VERSION 5.8 ;
BUSBITCHARS "[]" ;
DIVIDERCHAR "/" ;
UNITS
    DATABASE MICRONS 1000 ;
END UNITS

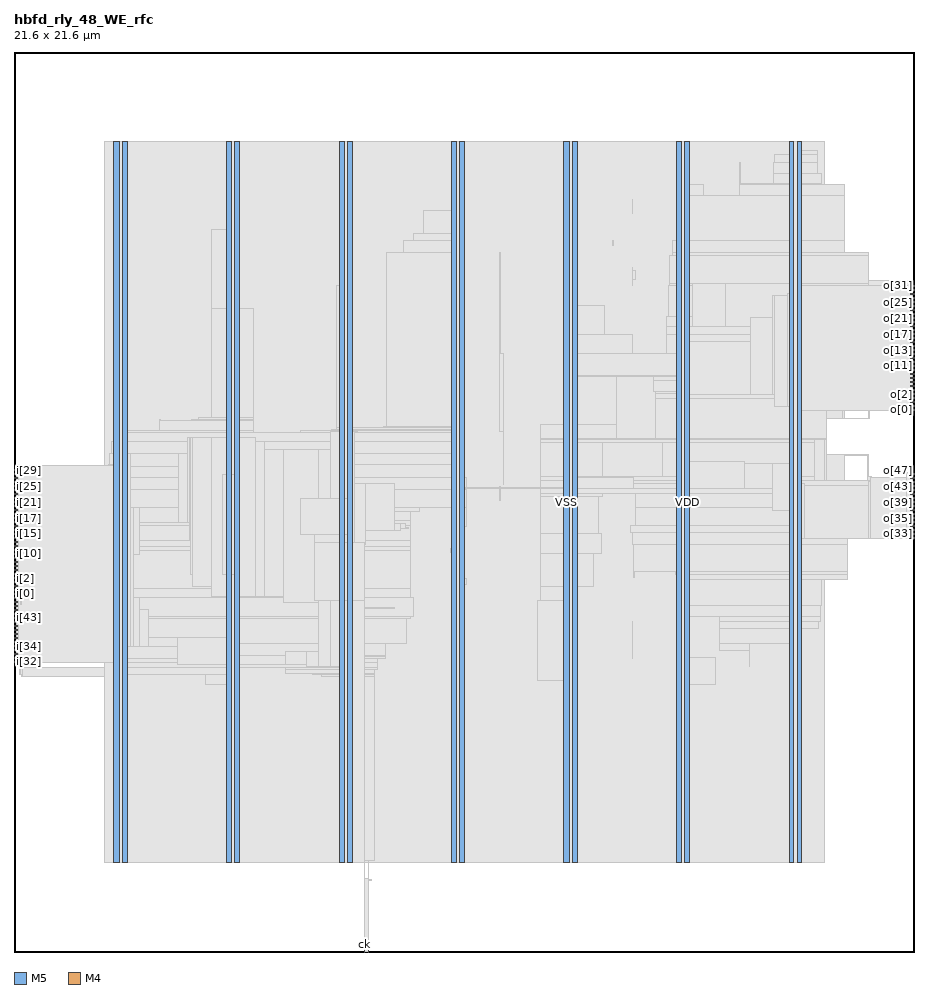
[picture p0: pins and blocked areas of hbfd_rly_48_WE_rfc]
MACRO hbfd_rly_48_WE_rfc
  FOREIGN hbfd_rly_48_WE_rfc 0 0 ;
  CLASS BLOCK ;
  SIZE 21.6 BY 21.6 ;
  PIN ck
    DIRECTION INPUT ;
    USE SIGNAL ;
    PORT
      LAYER M5 ;
        RECT  8.4 0 8.424 0.084 ;
    END
  END ck
  PIN i[0]
    DIRECTION INPUT ;
    USE SIGNAL ;
    PORT
      LAYER M4 ;
        RECT  0 8.592 0.084 8.616 ;
    END
  END i[0]
  PIN i[10]
    DIRECTION INPUT ;
    USE SIGNAL ;
    PORT
      LAYER M4 ;
        RECT  0 9.552 0.084 9.576 ;
    END
  END i[10]
  PIN i[11]
    DIRECTION INPUT ;
    USE SIGNAL ;
    PORT
      LAYER M4 ;
        RECT  0 9.648 0.084 9.672 ;
    END
  END i[11]
  PIN i[12]
    DIRECTION INPUT ;
    USE SIGNAL ;
    PORT
      LAYER M4 ;
        RECT  0 9.744 0.084 9.768 ;
    END
  END i[12]
  PIN i[13]
    DIRECTION INPUT ;
    USE SIGNAL ;
    PORT
      LAYER M4 ;
        RECT  0 9.84 0.084 9.864 ;
    END
  END i[13]
  PIN i[14]
    DIRECTION INPUT ;
    USE SIGNAL ;
    PORT
      LAYER M4 ;
        RECT  0 9.936 0.084 9.96 ;
    END
  END i[14]
  PIN i[15]
    DIRECTION INPUT ;
    USE SIGNAL ;
    PORT
      LAYER M4 ;
        RECT  0 10.032 0.084 10.056 ;
    END
  END i[15]
  PIN i[16]
    DIRECTION INPUT ;
    USE SIGNAL ;
    PORT
      LAYER M4 ;
        RECT  0 10.128 0.084 10.152 ;
    END
  END i[16]
  PIN i[17]
    DIRECTION INPUT ;
    USE SIGNAL ;
    PORT
      LAYER M4 ;
        RECT  0 10.224 0.084 10.248 ;
    END
  END i[17]
  PIN i[18]
    DIRECTION INPUT ;
    USE SIGNAL ;
    PORT
      LAYER M4 ;
        RECT  0 10.32 0.084 10.344 ;
    END
  END i[18]
  PIN i[19]
    DIRECTION INPUT ;
    USE SIGNAL ;
    PORT
      LAYER M4 ;
        RECT  0 10.416 0.084 10.44 ;
    END
  END i[19]
  PIN i[1]
    DIRECTION INPUT ;
    USE SIGNAL ;
    PORT
      LAYER M4 ;
        RECT  0 8.688 0.084 8.712 ;
    END
  END i[1]
  PIN i[20]
    DIRECTION INPUT ;
    USE SIGNAL ;
    PORT
      LAYER M4 ;
        RECT  0 10.512 0.084 10.536 ;
    END
  END i[20]
  PIN i[21]
    DIRECTION INPUT ;
    USE SIGNAL ;
    PORT
      LAYER M4 ;
        RECT  0 10.608 0.084 10.632 ;
    END
  END i[21]
  PIN i[22]
    DIRECTION INPUT ;
    USE SIGNAL ;
    PORT
      LAYER M4 ;
        RECT  0 10.704 0.084 10.728 ;
    END
  END i[22]
  PIN i[23]
    DIRECTION INPUT ;
    USE SIGNAL ;
    PORT
      LAYER M4 ;
        RECT  0 10.8 0.084 10.824 ;
    END
  END i[23]
  PIN i[24]
    DIRECTION INPUT ;
    USE SIGNAL ;
    PORT
      LAYER M4 ;
        RECT  0 10.896 0.084 10.92 ;
    END
  END i[24]
  PIN i[25]
    DIRECTION INPUT ;
    USE SIGNAL ;
    PORT
      LAYER M4 ;
        RECT  0 10.992 0.084 11.016 ;
    END
  END i[25]
  PIN i[26]
    DIRECTION INPUT ;
    USE SIGNAL ;
    PORT
      LAYER M4 ;
        RECT  0 11.088 0.084 11.112 ;
    END
  END i[26]
  PIN i[27]
    DIRECTION INPUT ;
    USE SIGNAL ;
    PORT
      LAYER M4 ;
        RECT  0 11.184 0.084 11.208 ;
    END
  END i[27]
  PIN i[28]
    DIRECTION INPUT ;
    USE SIGNAL ;
    PORT
      LAYER M4 ;
        RECT  0 11.28 0.084 11.304 ;
    END
  END i[28]
  PIN i[29]
    DIRECTION INPUT ;
    USE SIGNAL ;
    PORT
      LAYER M4 ;
        RECT  0 11.376 0.084 11.4 ;
    END
  END i[29]
  PIN i[2]
    DIRECTION INPUT ;
    USE SIGNAL ;
    PORT
      LAYER M4 ;
        RECT  0 8.784 0.084 8.808 ;
    END
  END i[2]
  PIN i[30]
    DIRECTION INPUT ;
    USE SIGNAL ;
    PORT
      LAYER M4 ;
        RECT  0 11.472 0.084 11.496 ;
    END
  END i[30]
  PIN i[31]
    DIRECTION INPUT ;
    USE SIGNAL ;
    PORT
      LAYER M4 ;
        RECT  0 11.568 0.084 11.592 ;
    END
  END i[31]
  PIN i[32]
    DIRECTION INPUT ;
    USE SIGNAL ;
    PORT
      LAYER M4 ;
        RECT  0 6.96 0.084 6.984 ;
    END
  END i[32]
  PIN i[33]
    DIRECTION INPUT ;
    USE SIGNAL ;
    PORT
      LAYER M4 ;
        RECT  0 7.056 0.084 7.08 ;
    END
  END i[33]
  PIN i[34]
    DIRECTION INPUT ;
    USE SIGNAL ;
    PORT
      LAYER M4 ;
        RECT  0 7.152 0.084 7.176 ;
    END
  END i[34]
  PIN i[35]
    DIRECTION INPUT ;
    USE SIGNAL ;
    PORT
      LAYER M4 ;
        RECT  0 7.248 0.084 7.272 ;
    END
  END i[35]
  PIN i[36]
    DIRECTION INPUT ;
    USE SIGNAL ;
    PORT
      LAYER M4 ;
        RECT  0 7.344 0.084 7.368 ;
    END
  END i[36]
  PIN i[37]
    DIRECTION INPUT ;
    USE SIGNAL ;
    PORT
      LAYER M4 ;
        RECT  0 7.44 0.084 7.464 ;
    END
  END i[37]
  PIN i[38]
    DIRECTION INPUT ;
    USE SIGNAL ;
    PORT
      LAYER M4 ;
        RECT  0 7.536 0.084 7.56 ;
    END
  END i[38]
  PIN i[39]
    DIRECTION INPUT ;
    USE SIGNAL ;
    PORT
      LAYER M4 ;
        RECT  0 7.632 0.084 7.656 ;
    END
  END i[39]
  PIN i[3]
    DIRECTION INPUT ;
    USE SIGNAL ;
    PORT
      LAYER M4 ;
        RECT  0 8.88 0.084 8.904 ;
    END
  END i[3]
  PIN i[40]
    DIRECTION INPUT ;
    USE SIGNAL ;
    PORT
      LAYER M4 ;
        RECT  0 7.728 0.084 7.752 ;
    END
  END i[40]
  PIN i[41]
    DIRECTION INPUT ;
    USE SIGNAL ;
    PORT
      LAYER M4 ;
        RECT  0 7.824 0.084 7.848 ;
    END
  END i[41]
  PIN i[42]
    DIRECTION INPUT ;
    USE SIGNAL ;
    PORT
      LAYER M4 ;
        RECT  0 7.92 0.084 7.944 ;
    END
  END i[42]
  PIN i[43]
    DIRECTION INPUT ;
    USE SIGNAL ;
    PORT
      LAYER M4 ;
        RECT  0 8.016 0.084 8.04 ;
    END
  END i[43]
  PIN i[44]
    DIRECTION INPUT ;
    USE SIGNAL ;
    PORT
      LAYER M4 ;
        RECT  0 8.112 0.084 8.136 ;
    END
  END i[44]
  PIN i[45]
    DIRECTION INPUT ;
    USE SIGNAL ;
    PORT
      LAYER M4 ;
        RECT  0 8.208 0.084 8.232 ;
    END
  END i[45]
  PIN i[46]
    DIRECTION INPUT ;
    USE SIGNAL ;
    PORT
      LAYER M4 ;
        RECT  0 8.304 0.084 8.328 ;
    END
  END i[46]
  PIN i[47]
    DIRECTION INPUT ;
    USE SIGNAL ;
    PORT
      LAYER M4 ;
        RECT  0 8.4 0.084 8.424 ;
    END
  END i[47]
  PIN i[4]
    DIRECTION INPUT ;
    USE SIGNAL ;
    PORT
      LAYER M4 ;
        RECT  0 8.976 0.084 9 ;
    END
  END i[4]
  PIN i[5]
    DIRECTION INPUT ;
    USE SIGNAL ;
    PORT
      LAYER M4 ;
        RECT  0 9.072 0.084 9.096 ;
    END
  END i[5]
  PIN i[6]
    DIRECTION INPUT ;
    USE SIGNAL ;
    PORT
      LAYER M4 ;
        RECT  0 9.168 0.084 9.192 ;
    END
  END i[6]
  PIN i[7]
    DIRECTION INPUT ;
    USE SIGNAL ;
    PORT
      LAYER M4 ;
        RECT  0 9.264 0.084 9.288 ;
    END
  END i[7]
  PIN i[8]
    DIRECTION INPUT ;
    USE SIGNAL ;
    PORT
      LAYER M4 ;
        RECT  0 9.36 0.084 9.384 ;
    END
  END i[8]
  PIN i[9]
    DIRECTION INPUT ;
    USE SIGNAL ;
    PORT
      LAYER M4 ;
        RECT  0 9.456 0.084 9.48 ;
    END
  END i[9]
  PIN o[0]
    DIRECTION OUTPUT ;
    USE SIGNAL ;
    PORT
      LAYER M4 ;
        RECT  21.516 13.008 21.6 13.032 ;
    END
  END o[0]
  PIN o[10]
    DIRECTION OUTPUT ;
    USE SIGNAL ;
    PORT
      LAYER M4 ;
        RECT  21.516 13.968 21.6 13.992 ;
    END
  END o[10]
  PIN o[11]
    DIRECTION OUTPUT ;
    USE SIGNAL ;
    PORT
      LAYER M4 ;
        RECT  21.516 14.064 21.6 14.088 ;
    END
  END o[11]
  PIN o[12]
    DIRECTION OUTPUT ;
    USE SIGNAL ;
    PORT
      LAYER M4 ;
        RECT  21.516 14.16 21.6 14.184 ;
    END
  END o[12]
  PIN o[13]
    DIRECTION OUTPUT ;
    USE SIGNAL ;
    PORT
      LAYER M4 ;
        RECT  21.516 14.256 21.6 14.28 ;
    END
  END o[13]
  PIN o[14]
    DIRECTION OUTPUT ;
    USE SIGNAL ;
    PORT
      LAYER M4 ;
        RECT  21.516 14.352 21.6 14.376 ;
    END
  END o[14]
  PIN o[15]
    DIRECTION OUTPUT ;
    USE SIGNAL ;
    PORT
      LAYER M4 ;
        RECT  21.516 14.448 21.6 14.472 ;
    END
  END o[15]
  PIN o[16]
    DIRECTION OUTPUT ;
    USE SIGNAL ;
    PORT
      LAYER M4 ;
        RECT  21.516 14.544 21.6 14.568 ;
    END
  END o[16]
  PIN o[17]
    DIRECTION OUTPUT ;
    USE SIGNAL ;
    PORT
      LAYER M4 ;
        RECT  21.516 14.64 21.6 14.664 ;
    END
  END o[17]
  PIN o[18]
    DIRECTION OUTPUT ;
    USE SIGNAL ;
    PORT
      LAYER M4 ;
        RECT  21.516 14.736 21.6 14.76 ;
    END
  END o[18]
  PIN o[19]
    DIRECTION OUTPUT ;
    USE SIGNAL ;
    PORT
      LAYER M4 ;
        RECT  21.516 14.832 21.6 14.856 ;
    END
  END o[19]
  PIN o[1]
    DIRECTION OUTPUT ;
    USE SIGNAL ;
    PORT
      LAYER M4 ;
        RECT  21.516 13.104 21.6 13.128 ;
    END
  END o[1]
  PIN o[20]
    DIRECTION OUTPUT ;
    USE SIGNAL ;
    PORT
      LAYER M4 ;
        RECT  21.516 14.928 21.6 14.952 ;
    END
  END o[20]
  PIN o[21]
    DIRECTION OUTPUT ;
    USE SIGNAL ;
    PORT
      LAYER M4 ;
        RECT  21.516 15.024 21.6 15.048 ;
    END
  END o[21]
  PIN o[22]
    DIRECTION OUTPUT ;
    USE SIGNAL ;
    PORT
      LAYER M4 ;
        RECT  21.516 15.12 21.6 15.144 ;
    END
  END o[22]
  PIN o[23]
    DIRECTION OUTPUT ;
    USE SIGNAL ;
    PORT
      LAYER M4 ;
        RECT  21.516 15.216 21.6 15.24 ;
    END
  END o[23]
  PIN o[24]
    DIRECTION OUTPUT ;
    USE SIGNAL ;
    PORT
      LAYER M4 ;
        RECT  21.516 15.312 21.6 15.336 ;
    END
  END o[24]
  PIN o[25]
    DIRECTION OUTPUT ;
    USE SIGNAL ;
    PORT
      LAYER M4 ;
        RECT  21.516 15.408 21.6 15.432 ;
    END
  END o[25]
  PIN o[26]
    DIRECTION OUTPUT ;
    USE SIGNAL ;
    PORT
      LAYER M4 ;
        RECT  21.516 15.504 21.6 15.528 ;
    END
  END o[26]
  PIN o[27]
    DIRECTION OUTPUT ;
    USE SIGNAL ;
    PORT
      LAYER M4 ;
        RECT  21.516 15.6 21.6 15.624 ;
    END
  END o[27]
  PIN o[28]
    DIRECTION OUTPUT ;
    USE SIGNAL ;
    PORT
      LAYER M4 ;
        RECT  21.516 15.696 21.6 15.72 ;
    END
  END o[28]
  PIN o[29]
    DIRECTION OUTPUT ;
    USE SIGNAL ;
    PORT
      LAYER M4 ;
        RECT  21.516 15.792 21.6 15.816 ;
    END
  END o[29]
  PIN o[2]
    DIRECTION OUTPUT ;
    USE SIGNAL ;
    PORT
      LAYER M4 ;
        RECT  21.516 13.2 21.6 13.224 ;
    END
  END o[2]
  PIN o[30]
    DIRECTION OUTPUT ;
    USE SIGNAL ;
    PORT
      LAYER M4 ;
        RECT  21.516 15.888 21.6 15.912 ;
    END
  END o[30]
  PIN o[31]
    DIRECTION OUTPUT ;
    USE SIGNAL ;
    PORT
      LAYER M4 ;
        RECT  21.516 15.984 21.6 16.008 ;
    END
  END o[31]
  PIN o[32]
    DIRECTION OUTPUT ;
    USE SIGNAL ;
    PORT
      LAYER M4 ;
        RECT  21.516 9.936 21.6 9.96 ;
    END
  END o[32]
  PIN o[33]
    DIRECTION OUTPUT ;
    USE SIGNAL ;
    PORT
      LAYER M4 ;
        RECT  21.516 10.032 21.6 10.056 ;
    END
  END o[33]
  PIN o[34]
    DIRECTION OUTPUT ;
    USE SIGNAL ;
    PORT
      LAYER M4 ;
        RECT  21.516 10.128 21.6 10.152 ;
    END
  END o[34]
  PIN o[35]
    DIRECTION OUTPUT ;
    USE SIGNAL ;
    PORT
      LAYER M4 ;
        RECT  21.516 10.224 21.6 10.248 ;
    END
  END o[35]
  PIN o[36]
    DIRECTION OUTPUT ;
    USE SIGNAL ;
    PORT
      LAYER M4 ;
        RECT  21.516 10.32 21.6 10.344 ;
    END
  END o[36]
  PIN o[37]
    DIRECTION OUTPUT ;
    USE SIGNAL ;
    PORT
      LAYER M4 ;
        RECT  21.516 10.416 21.6 10.44 ;
    END
  END o[37]
  PIN o[38]
    DIRECTION OUTPUT ;
    USE SIGNAL ;
    PORT
      LAYER M4 ;
        RECT  21.516 10.512 21.6 10.536 ;
    END
  END o[38]
  PIN o[39]
    DIRECTION OUTPUT ;
    USE SIGNAL ;
    PORT
      LAYER M4 ;
        RECT  21.516 10.608 21.6 10.632 ;
    END
  END o[39]
  PIN o[3]
    DIRECTION OUTPUT ;
    USE SIGNAL ;
    PORT
      LAYER M4 ;
        RECT  21.516 13.296 21.6 13.32 ;
    END
  END o[3]
  PIN o[40]
    DIRECTION OUTPUT ;
    USE SIGNAL ;
    PORT
      LAYER M4 ;
        RECT  21.516 10.704 21.6 10.728 ;
    END
  END o[40]
  PIN o[41]
    DIRECTION OUTPUT ;
    USE SIGNAL ;
    PORT
      LAYER M4 ;
        RECT  21.516 10.8 21.6 10.824 ;
    END
  END o[41]
  PIN o[42]
    DIRECTION OUTPUT ;
    USE SIGNAL ;
    PORT
      LAYER M4 ;
        RECT  21.516 10.896 21.6 10.92 ;
    END
  END o[42]
  PIN o[43]
    DIRECTION OUTPUT ;
    USE SIGNAL ;
    PORT
      LAYER M4 ;
        RECT  21.516 10.992 21.6 11.016 ;
    END
  END o[43]
  PIN o[44]
    DIRECTION OUTPUT ;
    USE SIGNAL ;
    PORT
      LAYER M4 ;
        RECT  21.516 11.088 21.6 11.112 ;
    END
  END o[44]
  PIN o[45]
    DIRECTION OUTPUT ;
    USE SIGNAL ;
    PORT
      LAYER M4 ;
        RECT  21.516 11.184 21.6 11.208 ;
    END
  END o[45]
  PIN o[46]
    DIRECTION OUTPUT ;
    USE SIGNAL ;
    PORT
      LAYER M4 ;
        RECT  21.516 11.28 21.6 11.304 ;
    END
  END o[46]
  PIN o[47]
    DIRECTION OUTPUT ;
    USE SIGNAL ;
    PORT
      LAYER M4 ;
        RECT  21.516 11.376 21.6 11.4 ;
    END
  END o[47]
  PIN o[4]
    DIRECTION OUTPUT ;
    USE SIGNAL ;
    PORT
      LAYER M4 ;
        RECT  21.516 13.392 21.6 13.416 ;
    END
  END o[4]
  PIN o[5]
    DIRECTION OUTPUT ;
    USE SIGNAL ;
    PORT
      LAYER M4 ;
        RECT  21.516 13.488 21.6 13.512 ;
    END
  END o[5]
  PIN o[6]
    DIRECTION OUTPUT ;
    USE SIGNAL ;
    PORT
      LAYER M4 ;
        RECT  21.516 13.584 21.6 13.608 ;
    END
  END o[6]
  PIN o[7]
    DIRECTION OUTPUT ;
    USE SIGNAL ;
    PORT
      LAYER M4 ;
        RECT  21.516 13.68 21.6 13.704 ;
    END
  END o[7]
  PIN o[8]
    DIRECTION OUTPUT ;
    USE SIGNAL ;
    PORT
      LAYER M4 ;
        RECT  21.516 13.776 21.6 13.8 ;
    END
  END o[8]
  PIN o[9]
    DIRECTION OUTPUT ;
    USE SIGNAL ;
    PORT
      LAYER M4 ;
        RECT  21.516 13.872 21.6 13.896 ;
    END
  END o[9]
  PIN rfi
    DIRECTION INPUT ;
    USE SIGNAL ;
    PORT
      LAYER M4 ;
        RECT  0 8.496 0.084 8.52 ;
    END
  END rfi
  PIN rfo
    DIRECTION OUTPUT ;
    USE SIGNAL ;
    PORT
      LAYER M4 ;
        RECT  21.516 11.472 21.6 11.496 ;
    END
  END rfo
  PIN rs
    DIRECTION INPUT ;
    USE SIGNAL ;
    PORT
      LAYER M5 ;
        RECT  8.496 0 8.52 0.084 ;
    END
  END rs
  PIN VDD
    DIRECTION INOUT ;
    USE POWER ;
    PORT
      LAYER M5 ;
        RECT  18.792 2.151 18.912 19.449 ;
        RECT  16.092 2.151 16.212 19.449 ;
        RECT  13.392 2.151 13.512 19.449 ;
        RECT  10.692 2.151 10.812 19.449 ;
        RECT  7.992 2.151 8.112 19.449 ;
        RECT  5.292 2.151 5.412 19.449 ;
        RECT  2.592 2.151 2.712 19.449 ;
    END
  END VDD
  PIN VSS
    DIRECTION INOUT ;
    USE GROUND ;
    PORT
      LAYER M5 ;
        RECT  18.6 2.137 18.72 19.463 ;
        RECT  15.9 2.137 16.02 19.463 ;
        RECT  13.2 2.137 13.32 19.463 ;
        RECT  10.5 2.137 10.62 19.463 ;
        RECT  7.8 2.137 7.92 19.463 ;
        RECT  5.1 2.137 5.22 19.463 ;
        RECT  2.4 2.137 2.52 19.463 ;
    END
  END VSS
  OBS
    LAYER RVTN ;
     RECT  2.16 2.16 19.44 2.295 ;
     RECT  2.16 2.565 19.44 2.835 ;
     RECT  2.16 3.105 19.44 3.375 ;
     RECT  2.16 3.645 19.44 3.915 ;
     RECT  2.16 4.185 19.44 4.455 ;
     RECT  2.16 4.725 19.44 4.995 ;
     RECT  2.16 5.265 19.44 5.535 ;
     RECT  2.16 5.805 19.44 6.075 ;
     RECT  2.16 6.345 19.44 6.615 ;
     RECT  2.16 6.885 19.44 7.155 ;
     RECT  2.16 7.425 19.44 7.695 ;
     RECT  2.16 7.965 19.44 8.235 ;
     RECT  2.16 8.505 19.44 8.775 ;
     RECT  2.16 9.045 19.44 9.315 ;
     RECT  2.16 9.585 19.44 9.855 ;
     RECT  2.16 10.125 19.44 10.395 ;
     RECT  2.16 10.665 19.44 10.935 ;
     RECT  2.16 11.205 19.44 11.475 ;
     RECT  2.16 11.745 19.44 12.015 ;
     RECT  2.16 12.285 19.44 12.555 ;
     RECT  2.16 12.825 19.44 13.095 ;
     RECT  2.16 13.365 19.44 13.635 ;
     RECT  2.16 13.905 19.44 14.175 ;
     RECT  2.16 14.445 19.44 14.715 ;
     RECT  2.16 14.985 19.44 15.255 ;
     RECT  2.16 15.525 19.44 15.795 ;
     RECT  2.16 16.065 19.44 16.335 ;
     RECT  2.16 16.605 19.44 16.875 ;
     RECT  2.16 17.145 19.44 17.415 ;
     RECT  2.16 17.685 19.44 17.955 ;
     RECT  2.16 18.225 19.44 18.495 ;
     RECT  2.16 18.765 19.44 19.035 ;
     RECT  2.16 19.305 19.44 19.44 ;
    LAYER RVTP ;
     RECT  2.16 2.295 19.44 2.565 ;
     RECT  2.16 2.835 19.44 3.105 ;
     RECT  2.16 3.375 19.44 3.645 ;
     RECT  2.16 3.915 19.44 4.185 ;
     RECT  2.16 4.455 19.44 4.725 ;
     RECT  2.16 4.995 19.44 5.265 ;
     RECT  2.16 5.535 19.44 5.805 ;
     RECT  2.16 6.075 19.44 6.345 ;
     RECT  2.16 6.615 19.44 6.885 ;
     RECT  2.16 7.155 19.44 7.425 ;
     RECT  2.16 7.695 19.44 7.965 ;
     RECT  2.16 8.235 19.44 8.505 ;
     RECT  2.16 8.775 19.44 9.045 ;
     RECT  2.16 9.315 19.44 9.585 ;
     RECT  2.16 9.855 19.44 10.125 ;
     RECT  2.16 10.395 19.44 10.665 ;
     RECT  2.16 10.935 19.44 11.205 ;
     RECT  2.16 11.475 19.44 11.745 ;
     RECT  2.16 12.015 19.44 12.285 ;
     RECT  2.16 12.555 19.44 12.825 ;
     RECT  2.16 13.095 19.44 13.365 ;
     RECT  2.16 13.635 19.44 13.905 ;
     RECT  2.16 14.175 19.44 14.445 ;
     RECT  2.16 14.715 19.44 14.985 ;
     RECT  2.16 15.255 19.44 15.525 ;
     RECT  2.16 15.795 19.44 16.065 ;
     RECT  2.16 16.335 19.44 16.605 ;
     RECT  2.16 16.875 19.44 17.145 ;
     RECT  2.16 17.415 19.44 17.685 ;
     RECT  2.16 17.955 19.44 18.225 ;
     RECT  2.16 18.495 19.44 18.765 ;
     RECT  2.16 19.035 19.44 19.305 ;
    LAYER M1 ;
     RECT  2.16 2.151 19.44 19.449 ;
    LAYER M2 ;
     RECT  0.103 6.822 0.139 6.84 ;
     RECT  0.139 6.66 0.175 6.84 ;
     RECT  0.175 6.624 2.16 6.84 ;
     RECT  0.535 8.28 2.16 8.298 ;
     RECT  1.147 10.332 2.16 10.35 ;
     RECT  2.16 2.151 19.44 19.449 ;
     RECT  19.44 10.476 19.499 17.064 ;
     RECT  19.499 12.798 19.895 17.064 ;
     RECT  19.499 10.476 19.931 11.934 ;
     RECT  19.895 12.798 19.931 16.794 ;
     RECT  19.44 18.396 19.931 18.414 ;
     RECT  19.44 8.946 19.967 9.27 ;
     RECT  19.967 8.946 20.003 8.964 ;
     RECT  19.931 11.916 20.507 11.934 ;
     RECT  19.931 13.644 20.507 16.794 ;
     RECT  19.931 12.798 20.543 12.816 ;
     RECT  20.507 13.806 20.543 14.274 ;
     RECT  19.931 10.674 20.579 11.034 ;
     RECT  20.543 13.806 21.415 13.824 ;
     RECT  20.507 15.066 21.479 16.128 ;
     RECT  20.579 11.016 21.515 11.034 ;
     RECT  21.415 13.806 21.515 14.094 ;
     RECT  21.479 15.066 21.515 15.084 ;
     RECT  21.479 16.11 21.515 16.128 ;
    LAYER M3 ;
     RECT  8.496 1.723 8.514 2.143 ;
     RECT  7.815 2.143 8.514 2.191 ;
     RECT  2.415 2.143 2.505 2.413 ;
     RECT  5.115 2.143 5.205 2.413 ;
     RECT  10.515 2.143 10.605 2.413 ;
     RECT  13.215 2.143 13.305 2.413 ;
     RECT  15.915 2.143 16.005 2.413 ;
     RECT  18.615 2.143 18.705 2.413 ;
     RECT  5.115 2.413 5.397 6.421 ;
     RECT  15.915 2.413 16.197 6.421 ;
     RECT  13.215 2.413 13.497 6.511 ;
     RECT  7.815 2.191 8.658 6.619 ;
     RECT  0.18 6.619 0.198 6.655 ;
     RECT  2.415 2.413 2.697 6.655 ;
     RECT  4.608 6.421 5.397 6.655 ;
     RECT  7.38 6.619 8.658 6.655 ;
     RECT  7.164 6.655 8.658 6.691 ;
     RECT  6.516 6.691 8.658 6.781 ;
     RECT  0.144 6.655 0.198 6.817 ;
     RECT  2.415 6.655 5.397 6.817 ;
     RECT  6.516 6.781 8.73 6.817 ;
     RECT  2.415 6.817 8.73 6.955 ;
     RECT  2.304 6.955 8.73 7.051 ;
     RECT  15.915 6.421 16.83 7.079 ;
     RECT  17.64 6.853 17.658 7.231 ;
     RECT  0.108 6.817 0.198 7.277 ;
     RECT  2.268 7.051 8.91 7.393 ;
     RECT  16.92 7.231 17.658 7.393 ;
     RECT  18.615 2.413 18.897 7.393 ;
     RECT  0.144 7.277 0.198 7.661 ;
     RECT  16.92 7.393 18.897 7.771 ;
     RECT  0.18 7.661 0.198 7.853 ;
     RECT  14.832 7.051 14.85 7.925 ;
     RECT  16.92 7.771 19.314 7.933 ;
     RECT  10.515 2.413 10.797 7.969 ;
     RECT  2.268 7.393 9.414 8.005 ;
     RECT  2.268 8.005 9.522 8.041 ;
     RECT  15.915 7.079 16.197 8.041 ;
     RECT  16.92 7.933 19.35 8.041 ;
     RECT  15.915 8.041 19.35 8.311 ;
     RECT  0.324 8.275 0.558 8.347 ;
     RECT  12.564 6.511 13.497 8.429 ;
     RECT  2.268 8.041 9.594 8.501 ;
     RECT  0.324 8.347 1.17 8.525 ;
     RECT  2.268 8.501 9.522 8.735 ;
     RECT  12.636 8.429 13.497 8.779 ;
     RECT  10.515 7.969 10.818 8.815 ;
     RECT  0.54 8.525 1.17 8.909 ;
     RECT  15.915 8.311 19.386 8.941 ;
     RECT  10.515 8.815 10.854 8.969 ;
     RECT  15.915 8.941 19.998 9.049 ;
     RECT  14.868 8.977 14.886 9.121 ;
     RECT  15.876 9.049 19.998 9.121 ;
     RECT  12.636 8.779 13.914 9.553 ;
     RECT  10.515 8.969 10.797 9.595 ;
     RECT  2.304 8.735 9.522 9.643 ;
     RECT  10.476 9.595 10.797 9.689 ;
     RECT  2.268 9.643 9.522 9.739 ;
     RECT  14.868 9.121 19.998 9.787 ;
     RECT  2.232 9.739 9.522 9.887 ;
     RECT  12.636 9.553 14.094 10.049 ;
     RECT  14.832 9.787 19.998 10.057 ;
     RECT  10.515 9.689 10.797 10.201 ;
     RECT  2.268 9.887 9.522 10.229 ;
     RECT  14.796 10.057 19.998 10.229 ;
     RECT  1.152 8.909 1.17 10.355 ;
     RECT  8.892 10.229 9.522 10.355 ;
     RECT  8.928 10.355 9.522 10.561 ;
     RECT  8.928 10.561 9.738 10.669 ;
     RECT  10.515 10.201 10.854 10.669 ;
     RECT  14.904 10.229 19.998 10.669 ;
     RECT  0.144 10.651 0.162 10.829 ;
     RECT  12.636 10.049 14.022 10.939 ;
     RECT  12.636 10.939 14.13 11.011 ;
     RECT  14.904 10.669 20.574 11.011 ;
     RECT  21.492 10.891 21.51 11.039 ;
     RECT  2.268 10.229 8.154 11.101 ;
     RECT  8.928 10.669 10.854 11.101 ;
     RECT  11.664 10.831 11.682 11.165 ;
     RECT  12.636 11.011 20.574 11.309 ;
     RECT  2.268 11.101 10.854 11.399 ;
     RECT  12.636 11.309 19.206 11.405 ;
     RECT  20.484 11.309 20.574 11.405 ;
     RECT  21.42 11.131 21.438 11.501 ;
     RECT  0.108 11.563 0.126 11.693 ;
     RECT  2.268 11.399 10.797 11.705 ;
     RECT  20.484 11.405 20.502 11.939 ;
     RECT  2.304 11.705 10.797 11.975 ;
     RECT  12.636 11.405 14.13 12.217 ;
     RECT  15.552 11.405 19.206 12.217 ;
     RECT  2.34 11.975 10.797 12.245 ;
     RECT  12.636 12.217 19.206 12.289 ;
     RECT  12.636 12.289 19.494 12.317 ;
     RECT  2.415 12.245 10.797 12.479 ;
     RECT  11.736 11.209 11.754 12.487 ;
     RECT  2.415 12.479 5.742 12.515 ;
     RECT  6.876 12.479 10.797 12.515 ;
     RECT  7.632 12.515 10.797 12.551 ;
     RECT  7.74 12.551 10.797 12.587 ;
     RECT  8.856 12.587 10.797 12.623 ;
     RECT  12.636 12.317 14.454 12.659 ;
     RECT  3.492 12.515 5.742 12.749 ;
     RECT  3.492 12.749 3.51 12.785 ;
     RECT  4.248 12.749 5.742 12.785 ;
     RECT  4.428 12.785 5.742 12.821 ;
     RECT  15.408 12.317 19.494 13.291 ;
     RECT  20.52 12.793 20.538 13.291 ;
     RECT  15.408 13.291 20.538 13.397 ;
     RECT  15.408 13.397 19.494 13.441 ;
     RECT  15.336 13.441 19.494 13.709 ;
     RECT  13.176 12.659 14.454 13.801 ;
     RECT  15.336 13.709 19.386 13.801 ;
     RECT  13.176 13.801 19.386 13.829 ;
     RECT  21.492 13.483 21.51 14.071 ;
     RECT  11.664 12.487 11.754 14.369 ;
     RECT  13.215 13.829 19.386 14.369 ;
     RECT  20.484 13.397 20.538 14.381 ;
     RECT  21.42 14.071 21.51 14.539 ;
     RECT  21.312 14.539 21.51 14.669 ;
     RECT  13.215 14.369 14.85 14.819 ;
     RECT  15.66 14.369 19.386 14.827 ;
     RECT  20.484 14.381 20.502 14.827 ;
     RECT  15.66 14.827 20.502 15.017 ;
     RECT  15.66 15.017 16.29 15.251 ;
     RECT  4.752 12.821 5.742 15.449 ;
     RECT  13.215 14.819 14.166 15.521 ;
     RECT  21.456 14.669 21.51 15.739 ;
     RECT  21.42 15.739 21.51 15.917 ;
     RECT  7.74 12.587 8.097 15.989 ;
     RECT  15.696 15.251 16.29 15.989 ;
     RECT  15.732 15.989 16.29 16.033 ;
     RECT  17.064 15.017 20.502 16.033 ;
     RECT  21.492 15.917 21.51 16.133 ;
     RECT  14.832 15.997 14.85 16.141 ;
     RECT  14.832 16.141 14.922 16.367 ;
     RECT  14.832 16.367 14.85 16.439 ;
     RECT  15.732 16.033 20.502 16.709 ;
     RECT  8.928 12.623 10.797 16.799 ;
     RECT  11.664 14.369 11.682 16.799 ;
     RECT  15.804 16.709 20.502 16.799 ;
     RECT  9.36 16.799 10.797 17.069 ;
     RECT  14.364 16.951 14.382 17.069 ;
     RECT  15.804 16.799 19.926 17.069 ;
     RECT  9.576 17.069 10.797 17.249 ;
     RECT  4.752 15.449 5.397 17.339 ;
     RECT  9.828 17.249 10.797 17.789 ;
     RECT  14.832 17.725 14.85 18.059 ;
     RECT  15.915 17.069 19.926 18.149 ;
     RECT  15.915 18.149 16.542 18.419 ;
     RECT  17.424 18.149 19.926 18.419 ;
     RECT  17.424 18.419 19.386 18.455 ;
     RECT  18.216 18.455 19.386 18.689 ;
     RECT  17.424 18.455 17.442 18.959 ;
     RECT  18.216 18.689 19.278 18.959 ;
     RECT  18.252 18.959 19.278 19.139 ;
     RECT  2.415 12.515 2.697 19.187 ;
     RECT  5.115 17.339 5.397 19.187 ;
     RECT  7.815 15.989 8.097 19.187 ;
     RECT  10.515 17.789 10.797 19.187 ;
     RECT  13.215 15.521 13.497 19.187 ;
     RECT  15.915 18.419 16.197 19.187 ;
     RECT  18.615 19.139 19.278 19.229 ;
     RECT  2.415 19.187 2.505 19.457 ;
     RECT  5.115 19.187 5.205 19.457 ;
     RECT  7.815 19.187 7.905 19.457 ;
     RECT  10.515 19.187 10.605 19.457 ;
     RECT  13.215 19.187 13.305 19.457 ;
     RECT  15.915 19.187 16.005 19.457 ;
     RECT  18.615 19.229 18.705 19.457 ;
    LAYER M4 ;
     RECT  0.06 6.96 0.097 11.592 ;
     RECT  0.097 6.96 2.408 11.688 ;
     RECT  2.408 2.148 2.512 19.452 ;
     RECT  2.512 2.418 2.704 19.182 ;
     RECT  2.704 7.344 2.801 11.976 ;
     RECT  2.801 7.344 2.873 10.68 ;
     RECT  2.873 7.344 3.017 8.52 ;
     RECT  2.873 9.552 3.017 10.68 ;
     RECT  3.017 7.344 3.233 8.232 ;
     RECT  3.233 7.344 3.913 7.56 ;
     RECT  3.017 10.32 3.949 10.68 ;
     RECT  2.801 11.664 3.949 11.976 ;
     RECT  3.949 10.32 4.165 11.976 ;
     RECT  4.165 10.32 4.201 12.36 ;
     RECT  4.201 9.888 4.237 12.36 ;
     RECT  4.237 9.072 4.273 12.36 ;
     RECT  4.273 8.784 4.741 12.36 ;
     RECT  3.913 6.912 5.108 7.56 ;
     RECT  4.741 8.544 5.108 12.36 ;
     RECT  5.108 2.148 5.212 19.452 ;
     RECT  5.212 2.418 5.404 19.182 ;
     RECT  5.404 8.544 5.789 12.36 ;
     RECT  5.789 8.544 6.005 12.264 ;
     RECT  6.005 8.544 6.469 12.072 ;
     RECT  5.404 6.912 6.505 7.128 ;
     RECT  6.505 6.912 7.009 7.224 ;
     RECT  7.009 6.864 7.297 7.224 ;
     RECT  6.469 8.4 7.297 12.072 ;
     RECT  7.297 6.864 7.585 12.072 ;
     RECT  7.585 6.864 7.808 12.504 ;
     RECT  7.808 2.148 7.912 19.452 ;
     RECT  7.912 2.148 8.104 19.182 ;
     RECT  8.104 9.792 8.165 12.504 ;
     RECT  8.104 6.912 8.237 7.128 ;
     RECT  8.165 12.48 8.237 12.504 ;
     RECT  8.165 9.792 8.435 11.256 ;
     RECT  8.485 1.728 8.569 1.752 ;
     RECT  8.237 7.104 8.921 7.128 ;
     RECT  8.104 8.256 9.137 8.28 ;
     RECT  8.435 10.128 9.137 11.256 ;
     RECT  9.137 10.128 9.281 10.296 ;
     RECT  9.281 10.176 9.389 10.296 ;
     RECT  9.389 10.176 9.461 10.2 ;
     RECT  10.465 9.6 10.508 9.624 ;
     RECT  10.508 2.148 10.612 19.452 ;
     RECT  10.612 2.418 10.804 19.182 ;
     RECT  10.804 11.136 13.208 11.16 ;
     RECT  13.208 2.148 13.312 19.452 ;
     RECT  13.312 2.418 13.504 19.182 ;
     RECT  13.504 11.136 14.861 11.4 ;
     RECT  14.861 11.136 15.908 11.256 ;
     RECT  15.908 2.148 16.012 19.452 ;
     RECT  16.012 2.418 16.204 19.182 ;
     RECT  16.204 11.136 17.525 11.784 ;
     RECT  16.204 13.392 17.665 14.664 ;
     RECT  17.525 11.136 18.205 11.736 ;
     RECT  17.665 13.392 18.205 15.24 ;
     RECT  18.205 13.392 18.241 15.768 ;
     RECT  18.241 13.104 18.565 15.768 ;
     RECT  18.205 10.608 18.608 11.736 ;
     RECT  18.565 13.104 18.608 15.816 ;
     RECT  18.608 2.148 18.712 19.452 ;
     RECT  18.712 2.418 18.904 19.182 ;
     RECT  18.904 9.936 18.965 11.256 ;
     RECT  18.965 9.936 20.509 11.208 ;
     RECT  20.509 9.936 20.545 11.304 ;
     RECT  20.545 9.936 21.409 11.4 ;
     RECT  21.409 9.936 21.564 11.496 ;
     RECT  18.904 13.008 21.564 16.008 ;
    LAYER M5 ;
     RECT  8.4 0.016 8.52 1.763 ;
     RECT  8.4 1.763 8.424 2.137 ;
     RECT  2.4 2.137 2.52 2.151 ;
     RECT  5.1 2.137 5.22 2.151 ;
     RECT  10.5 2.137 10.62 2.151 ;
     RECT  13.2 2.137 13.32 2.151 ;
     RECT  15.9 2.137 16.02 2.151 ;
     RECT  18.6 2.137 18.72 2.151 ;
     RECT  7.8 2.137 8.424 8.437 ;
     RECT  0.144 8.341 0.168 8.531 ;
     RECT  5.1 2.151 5.412 9.061 ;
     RECT  7.2 8.437 8.424 9.827 ;
     RECT  7.2 9.827 8.112 10.021 ;
     RECT  6.864 10.021 8.112 10.883 ;
     RECT  4.992 9.061 5.412 11.459 ;
     RECT  2.4 2.151 2.712 19.449 ;
     RECT  5.1 11.459 5.412 19.449 ;
     RECT  7.8 10.883 8.112 19.449 ;
     RECT  10.5 2.151 10.812 19.449 ;
     RECT  13.2 2.151 13.512 19.449 ;
     RECT  15.9 2.151 16.212 19.449 ;
     RECT  18.6 2.151 18.912 19.449 ;
     RECT  2.4 19.449 2.52 19.463 ;
     RECT  5.1 19.449 5.22 19.463 ;
     RECT  7.8 19.449 7.92 19.463 ;
     RECT  10.5 19.449 10.62 19.463 ;
     RECT  13.2 19.449 13.32 19.463 ;
     RECT  15.9 19.449 16.02 19.463 ;
     RECT  18.6 19.449 18.72 19.463 ;
  END
END hbfd_rly_48_WE_rfc
END LIBRARY
